# OpenTallas memory compiler (tools/mem_compiler), ASAP7 abstract view, track-aligned v2 (build_aligned_v2.py)
VERSION 5.7 ;
BUSBITCHARS "[]" ;
DIVIDERCHAR "/" ;
PROPERTYDEFINITIONS
  MACRO width INTEGER ;
  MACRO depth INTEGER ;
  MACRO banks INTEGER ;
END PROPERTYDEFINITIONS
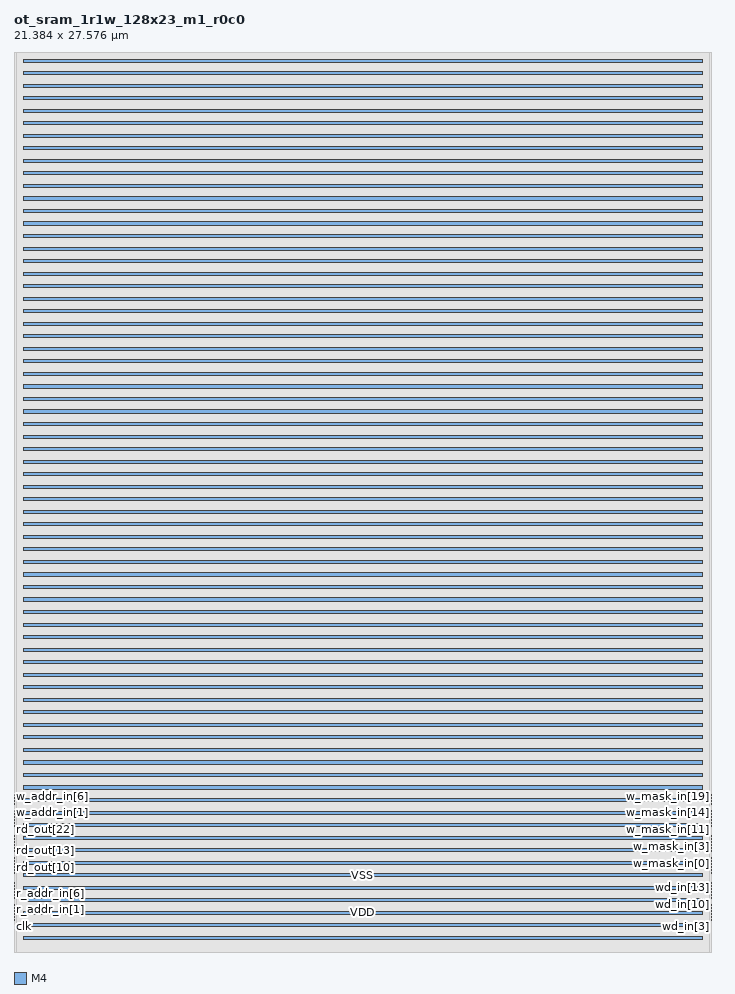
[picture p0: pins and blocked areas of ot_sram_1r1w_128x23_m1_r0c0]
MACRO ot_sram_1r1w_128x23_m1_r0c0
  PROPERTY width 23 ;
  PROPERTY depth 128 ;
  PROPERTY banks 1 ;
  FOREIGN ot_sram_1r1w_128x23_m1_r0c0 0 0 ;
  SYMMETRY X Y ;
  SIZE 21.384 BY 27.576 ;
  CLASS BLOCK ;
  PIN clk
    DIRECTION INPUT ;
    USE CLOCK ;
    SHAPE ABUTMENT ;
    PORT
      LAYER M4 ;
      RECT 0.000 0.768 0.024 0.792 ;
    END
  END clk
  PIN r_ce_in
    DIRECTION INPUT ;
    USE SIGNAL ;
    SHAPE ABUTMENT ;
    PORT
      LAYER M4 ;
      RECT 0.000 0.864 0.024 0.888 ;
    END
  END r_ce_in
  PIN r_addr_in[0]
    DIRECTION INPUT ;
    USE SIGNAL ;
    SHAPE ABUTMENT ;
    PORT
      LAYER M4 ;
      RECT 0.000 0.960 0.024 0.984 ;
    END
  END r_addr_in[0]
  PIN r_addr_in[1]
    DIRECTION INPUT ;
    USE SIGNAL ;
    SHAPE ABUTMENT ;
    PORT
      LAYER M4 ;
      RECT 0.000 1.056 0.024 1.080 ;
    END
  END r_addr_in[1]
  PIN r_addr_in[2]
    DIRECTION INPUT ;
    USE SIGNAL ;
    SHAPE ABUTMENT ;
    PORT
      LAYER M4 ;
      RECT 0.000 1.152 0.024 1.176 ;
    END
  END r_addr_in[2]
  PIN r_addr_in[3]
    DIRECTION INPUT ;
    USE SIGNAL ;
    SHAPE ABUTMENT ;
    PORT
      LAYER M4 ;
      RECT 0.000 1.248 0.024 1.272 ;
    END
  END r_addr_in[3]
  PIN r_addr_in[4]
    DIRECTION INPUT ;
    USE SIGNAL ;
    SHAPE ABUTMENT ;
    PORT
      LAYER M4 ;
      RECT 0.000 1.344 0.024 1.368 ;
    END
  END r_addr_in[4]
  PIN r_addr_in[5]
    DIRECTION INPUT ;
    USE SIGNAL ;
    SHAPE ABUTMENT ;
    PORT
      LAYER M4 ;
      RECT 0.000 1.440 0.024 1.464 ;
    END
  END r_addr_in[5]
  PIN r_addr_in[6]
    DIRECTION INPUT ;
    USE SIGNAL ;
    SHAPE ABUTMENT ;
    PORT
      LAYER M4 ;
      RECT 0.000 1.536 0.024 1.560 ;
    END
  END r_addr_in[6]
  PIN rd_out[0]
    DIRECTION OUTPUT ;
    USE SIGNAL ;
    SHAPE ABUTMENT ;
    PORT
      LAYER M4 ;
      RECT 0.000 1.632 0.024 1.656 ;
    END
  END rd_out[0]
  PIN rd_out[1]
    DIRECTION OUTPUT ;
    USE SIGNAL ;
    SHAPE ABUTMENT ;
    PORT
      LAYER M4 ;
      RECT 0.000 1.728 0.024 1.752 ;
    END
  END rd_out[1]
  PIN rd_out[2]
    DIRECTION OUTPUT ;
    USE SIGNAL ;
    SHAPE ABUTMENT ;
    PORT
      LAYER M4 ;
      RECT 0.000 1.824 0.024 1.848 ;
    END
  END rd_out[2]
  PIN rd_out[3]
    DIRECTION OUTPUT ;
    USE SIGNAL ;
    SHAPE ABUTMENT ;
    PORT
      LAYER M4 ;
      RECT 0.000 1.920 0.024 1.944 ;
    END
  END rd_out[3]
  PIN rd_out[4]
    DIRECTION OUTPUT ;
    USE SIGNAL ;
    SHAPE ABUTMENT ;
    PORT
      LAYER M4 ;
      RECT 0.000 2.016 0.024 2.040 ;
    END
  END rd_out[4]
  PIN rd_out[5]
    DIRECTION OUTPUT ;
    USE SIGNAL ;
    SHAPE ABUTMENT ;
    PORT
      LAYER M4 ;
      RECT 0.000 2.112 0.024 2.136 ;
    END
  END rd_out[5]
  PIN rd_out[6]
    DIRECTION OUTPUT ;
    USE SIGNAL ;
    SHAPE ABUTMENT ;
    PORT
      LAYER M4 ;
      RECT 0.000 2.208 0.024 2.232 ;
    END
  END rd_out[6]
  PIN rd_out[7]
    DIRECTION OUTPUT ;
    USE SIGNAL ;
    SHAPE ABUTMENT ;
    PORT
      LAYER M4 ;
      RECT 0.000 2.304 0.024 2.328 ;
    END
  END rd_out[7]
  PIN rd_out[8]
    DIRECTION OUTPUT ;
    USE SIGNAL ;
    SHAPE ABUTMENT ;
    PORT
      LAYER M4 ;
      RECT 0.000 2.400 0.024 2.424 ;
    END
  END rd_out[8]
  PIN rd_out[9]
    DIRECTION OUTPUT ;
    USE SIGNAL ;
    SHAPE ABUTMENT ;
    PORT
      LAYER M4 ;
      RECT 0.000 2.496 0.024 2.520 ;
    END
  END rd_out[9]
  PIN rd_out[10]
    DIRECTION OUTPUT ;
    USE SIGNAL ;
    SHAPE ABUTMENT ;
    PORT
      LAYER M4 ;
      RECT 0.000 2.592 0.024 2.616 ;
    END
  END rd_out[10]
  PIN rd_out[11]
    DIRECTION OUTPUT ;
    USE SIGNAL ;
    SHAPE ABUTMENT ;
    PORT
      LAYER M4 ;
      RECT 0.000 2.688 0.024 2.712 ;
    END
  END rd_out[11]
  PIN rd_out[12]
    DIRECTION OUTPUT ;
    USE SIGNAL ;
    SHAPE ABUTMENT ;
    PORT
      LAYER M4 ;
      RECT 0.000 2.784 0.024 2.808 ;
    END
  END rd_out[12]
  PIN rd_out[13]
    DIRECTION OUTPUT ;
    USE SIGNAL ;
    SHAPE ABUTMENT ;
    PORT
      LAYER M4 ;
      RECT 0.000 2.880 0.024 2.904 ;
    END
  END rd_out[13]
  PIN rd_out[14]
    DIRECTION OUTPUT ;
    USE SIGNAL ;
    SHAPE ABUTMENT ;
    PORT
      LAYER M4 ;
      RECT 0.000 2.976 0.024 3.000 ;
    END
  END rd_out[14]
  PIN rd_out[15]
    DIRECTION OUTPUT ;
    USE SIGNAL ;
    SHAPE ABUTMENT ;
    PORT
      LAYER M4 ;
      RECT 0.000 3.072 0.024 3.096 ;
    END
  END rd_out[15]
  PIN rd_out[16]
    DIRECTION OUTPUT ;
    USE SIGNAL ;
    SHAPE ABUTMENT ;
    PORT
      LAYER M4 ;
      RECT 0.000 3.168 0.024 3.192 ;
    END
  END rd_out[16]
  PIN rd_out[17]
    DIRECTION OUTPUT ;
    USE SIGNAL ;
    SHAPE ABUTMENT ;
    PORT
      LAYER M4 ;
      RECT 0.000 3.264 0.024 3.288 ;
    END
  END rd_out[17]
  PIN rd_out[18]
    DIRECTION OUTPUT ;
    USE SIGNAL ;
    SHAPE ABUTMENT ;
    PORT
      LAYER M4 ;
      RECT 0.000 3.360 0.024 3.384 ;
    END
  END rd_out[18]
  PIN rd_out[19]
    DIRECTION OUTPUT ;
    USE SIGNAL ;
    SHAPE ABUTMENT ;
    PORT
      LAYER M4 ;
      RECT 0.000 3.456 0.024 3.480 ;
    END
  END rd_out[19]
  PIN rd_out[20]
    DIRECTION OUTPUT ;
    USE SIGNAL ;
    SHAPE ABUTMENT ;
    PORT
      LAYER M4 ;
      RECT 0.000 3.552 0.024 3.576 ;
    END
  END rd_out[20]
  PIN rd_out[21]
    DIRECTION OUTPUT ;
    USE SIGNAL ;
    SHAPE ABUTMENT ;
    PORT
      LAYER M4 ;
      RECT 0.000 3.648 0.024 3.672 ;
    END
  END rd_out[21]
  PIN rd_out[22]
    DIRECTION OUTPUT ;
    USE SIGNAL ;
    SHAPE ABUTMENT ;
    PORT
      LAYER M4 ;
      RECT 0.000 3.744 0.024 3.768 ;
    END
  END rd_out[22]
  PIN w_ce_in
    DIRECTION INPUT ;
    USE SIGNAL ;
    SHAPE ABUTMENT ;
    PORT
      LAYER M4 ;
      RECT 0.000 3.840 0.024 3.864 ;
    END
  END w_ce_in
  PIN w_addr_in[0]
    DIRECTION INPUT ;
    USE SIGNAL ;
    SHAPE ABUTMENT ;
    PORT
      LAYER M4 ;
      RECT 0.000 3.936 0.024 3.960 ;
    END
  END w_addr_in[0]
  PIN w_addr_in[1]
    DIRECTION INPUT ;
    USE SIGNAL ;
    SHAPE ABUTMENT ;
    PORT
      LAYER M4 ;
      RECT 0.000 4.032 0.024 4.056 ;
    END
  END w_addr_in[1]
  PIN w_addr_in[2]
    DIRECTION INPUT ;
    USE SIGNAL ;
    SHAPE ABUTMENT ;
    PORT
      LAYER M4 ;
      RECT 0.000 4.128 0.024 4.152 ;
    END
  END w_addr_in[2]
  PIN w_addr_in[3]
    DIRECTION INPUT ;
    USE SIGNAL ;
    SHAPE ABUTMENT ;
    PORT
      LAYER M4 ;
      RECT 0.000 4.224 0.024 4.248 ;
    END
  END w_addr_in[3]
  PIN w_addr_in[4]
    DIRECTION INPUT ;
    USE SIGNAL ;
    SHAPE ABUTMENT ;
    PORT
      LAYER M4 ;
      RECT 0.000 4.320 0.024 4.344 ;
    END
  END w_addr_in[4]
  PIN w_addr_in[5]
    DIRECTION INPUT ;
    USE SIGNAL ;
    SHAPE ABUTMENT ;
    PORT
      LAYER M4 ;
      RECT 0.000 4.416 0.024 4.440 ;
    END
  END w_addr_in[5]
  PIN w_addr_in[6]
    DIRECTION INPUT ;
    USE SIGNAL ;
    SHAPE ABUTMENT ;
    PORT
      LAYER M4 ;
      RECT 0.000 4.512 0.024 4.536 ;
    END
  END w_addr_in[6]
  PIN wd_in[0]
    DIRECTION INPUT ;
    USE SIGNAL ;
    SHAPE ABUTMENT ;
    PORT
      LAYER M4 ;
      RECT 0.000 4.608 0.024 4.632 ;
    END
  END wd_in[0]
  PIN wd_in[1]
    DIRECTION INPUT ;
    USE SIGNAL ;
    SHAPE ABUTMENT ;
    PORT
      LAYER M4 ;
      RECT 0.000 4.704 0.024 4.728 ;
    END
  END wd_in[1]
  PIN wd_in[2]
    DIRECTION INPUT ;
    USE SIGNAL ;
    SHAPE ABUTMENT ;
    PORT
      LAYER M4 ;
      RECT 0.000 4.800 0.024 4.824 ;
    END
  END wd_in[2]
  PIN wd_in[3]
    DIRECTION INPUT ;
    USE SIGNAL ;
    SHAPE ABUTMENT ;
    PORT
      LAYER M4 ;
      RECT 21.360 0.768 21.384 0.792 ;
    END
  END wd_in[3]
  PIN wd_in[4]
    DIRECTION INPUT ;
    USE SIGNAL ;
    SHAPE ABUTMENT ;
    PORT
      LAYER M4 ;
      RECT 21.360 0.864 21.384 0.888 ;
    END
  END wd_in[4]
  PIN wd_in[5]
    DIRECTION INPUT ;
    USE SIGNAL ;
    SHAPE ABUTMENT ;
    PORT
      LAYER M4 ;
      RECT 21.360 0.960 21.384 0.984 ;
    END
  END wd_in[5]
  PIN wd_in[6]
    DIRECTION INPUT ;
    USE SIGNAL ;
    SHAPE ABUTMENT ;
    PORT
      LAYER M4 ;
      RECT 21.360 1.056 21.384 1.080 ;
    END
  END wd_in[6]
  PIN wd_in[7]
    DIRECTION INPUT ;
    USE SIGNAL ;
    SHAPE ABUTMENT ;
    PORT
      LAYER M4 ;
      RECT 21.360 1.152 21.384 1.176 ;
    END
  END wd_in[7]
  PIN wd_in[8]
    DIRECTION INPUT ;
    USE SIGNAL ;
    SHAPE ABUTMENT ;
    PORT
      LAYER M4 ;
      RECT 21.360 1.248 21.384 1.272 ;
    END
  END wd_in[8]
  PIN wd_in[9]
    DIRECTION INPUT ;
    USE SIGNAL ;
    SHAPE ABUTMENT ;
    PORT
      LAYER M4 ;
      RECT 21.360 1.344 21.384 1.368 ;
    END
  END wd_in[9]
  PIN wd_in[10]
    DIRECTION INPUT ;
    USE SIGNAL ;
    SHAPE ABUTMENT ;
    PORT
      LAYER M4 ;
      RECT 21.360 1.440 21.384 1.464 ;
    END
  END wd_in[10]
  PIN wd_in[11]
    DIRECTION INPUT ;
    USE SIGNAL ;
    SHAPE ABUTMENT ;
    PORT
      LAYER M4 ;
      RECT 21.360 1.536 21.384 1.560 ;
    END
  END wd_in[11]
  PIN wd_in[12]
    DIRECTION INPUT ;
    USE SIGNAL ;
    SHAPE ABUTMENT ;
    PORT
      LAYER M4 ;
      RECT 21.360 1.632 21.384 1.656 ;
    END
  END wd_in[12]
  PIN wd_in[13]
    DIRECTION INPUT ;
    USE SIGNAL ;
    SHAPE ABUTMENT ;
    PORT
      LAYER M4 ;
      RECT 21.360 1.728 21.384 1.752 ;
    END
  END wd_in[13]
  PIN wd_in[14]
    DIRECTION INPUT ;
    USE SIGNAL ;
    SHAPE ABUTMENT ;
    PORT
      LAYER M4 ;
      RECT 21.360 1.824 21.384 1.848 ;
    END
  END wd_in[14]
  PIN wd_in[15]
    DIRECTION INPUT ;
    USE SIGNAL ;
    SHAPE ABUTMENT ;
    PORT
      LAYER M4 ;
      RECT 21.360 1.920 21.384 1.944 ;
    END
  END wd_in[15]
  PIN wd_in[16]
    DIRECTION INPUT ;
    USE SIGNAL ;
    SHAPE ABUTMENT ;
    PORT
      LAYER M4 ;
      RECT 21.360 2.016 21.384 2.040 ;
    END
  END wd_in[16]
  PIN wd_in[17]
    DIRECTION INPUT ;
    USE SIGNAL ;
    SHAPE ABUTMENT ;
    PORT
      LAYER M4 ;
      RECT 21.360 2.112 21.384 2.136 ;
    END
  END wd_in[17]
  PIN wd_in[18]
    DIRECTION INPUT ;
    USE SIGNAL ;
    SHAPE ABUTMENT ;
    PORT
      LAYER M4 ;
      RECT 21.360 2.208 21.384 2.232 ;
    END
  END wd_in[18]
  PIN wd_in[19]
    DIRECTION INPUT ;
    USE SIGNAL ;
    SHAPE ABUTMENT ;
    PORT
      LAYER M4 ;
      RECT 21.360 2.304 21.384 2.328 ;
    END
  END wd_in[19]
  PIN wd_in[20]
    DIRECTION INPUT ;
    USE SIGNAL ;
    SHAPE ABUTMENT ;
    PORT
      LAYER M4 ;
      RECT 21.360 2.400 21.384 2.424 ;
    END
  END wd_in[20]
  PIN wd_in[21]
    DIRECTION INPUT ;
    USE SIGNAL ;
    SHAPE ABUTMENT ;
    PORT
      LAYER M4 ;
      RECT 21.360 2.496 21.384 2.520 ;
    END
  END wd_in[21]
  PIN wd_in[22]
    DIRECTION INPUT ;
    USE SIGNAL ;
    SHAPE ABUTMENT ;
    PORT
      LAYER M4 ;
      RECT 21.360 2.592 21.384 2.616 ;
    END
  END wd_in[22]
  PIN w_mask_in[0]
    DIRECTION INPUT ;
    USE SIGNAL ;
    SHAPE ABUTMENT ;
    PORT
      LAYER M4 ;
      RECT 21.360 2.688 21.384 2.712 ;
    END
  END w_mask_in[0]
  PIN w_mask_in[1]
    DIRECTION INPUT ;
    USE SIGNAL ;
    SHAPE ABUTMENT ;
    PORT
      LAYER M4 ;
      RECT 21.360 2.784 21.384 2.808 ;
    END
  END w_mask_in[1]
  PIN w_mask_in[2]
    DIRECTION INPUT ;
    USE SIGNAL ;
    SHAPE ABUTMENT ;
    PORT
      LAYER M4 ;
      RECT 21.360 2.880 21.384 2.904 ;
    END
  END w_mask_in[2]
  PIN w_mask_in[3]
    DIRECTION INPUT ;
    USE SIGNAL ;
    SHAPE ABUTMENT ;
    PORT
      LAYER M4 ;
      RECT 21.360 2.976 21.384 3.000 ;
    END
  END w_mask_in[3]
  PIN w_mask_in[4]
    DIRECTION INPUT ;
    USE SIGNAL ;
    SHAPE ABUTMENT ;
    PORT
      LAYER M4 ;
      RECT 21.360 3.072 21.384 3.096 ;
    END
  END w_mask_in[4]
  PIN w_mask_in[5]
    DIRECTION INPUT ;
    USE SIGNAL ;
    SHAPE ABUTMENT ;
    PORT
      LAYER M4 ;
      RECT 21.360 3.168 21.384 3.192 ;
    END
  END w_mask_in[5]
  PIN w_mask_in[6]
    DIRECTION INPUT ;
    USE SIGNAL ;
    SHAPE ABUTMENT ;
    PORT
      LAYER M4 ;
      RECT 21.360 3.264 21.384 3.288 ;
    END
  END w_mask_in[6]
  PIN w_mask_in[7]
    DIRECTION INPUT ;
    USE SIGNAL ;
    SHAPE ABUTMENT ;
    PORT
      LAYER M4 ;
      RECT 21.360 3.360 21.384 3.384 ;
    END
  END w_mask_in[7]
  PIN w_mask_in[8]
    DIRECTION INPUT ;
    USE SIGNAL ;
    SHAPE ABUTMENT ;
    PORT
      LAYER M4 ;
      RECT 21.360 3.456 21.384 3.480 ;
    END
  END w_mask_in[8]
  PIN w_mask_in[9]
    DIRECTION INPUT ;
    USE SIGNAL ;
    SHAPE ABUTMENT ;
    PORT
      LAYER M4 ;
      RECT 21.360 3.552 21.384 3.576 ;
    END
  END w_mask_in[9]
  PIN w_mask_in[10]
    DIRECTION INPUT ;
    USE SIGNAL ;
    SHAPE ABUTMENT ;
    PORT
      LAYER M4 ;
      RECT 21.360 3.648 21.384 3.672 ;
    END
  END w_mask_in[10]
  PIN w_mask_in[11]
    DIRECTION INPUT ;
    USE SIGNAL ;
    SHAPE ABUTMENT ;
    PORT
      LAYER M4 ;
      RECT 21.360 3.744 21.384 3.768 ;
    END
  END w_mask_in[11]
  PIN w_mask_in[12]
    DIRECTION INPUT ;
    USE SIGNAL ;
    SHAPE ABUTMENT ;
    PORT
      LAYER M4 ;
      RECT 21.360 3.840 21.384 3.864 ;
    END
  END w_mask_in[12]
  PIN w_mask_in[13]
    DIRECTION INPUT ;
    USE SIGNAL ;
    SHAPE ABUTMENT ;
    PORT
      LAYER M4 ;
      RECT 21.360 3.936 21.384 3.960 ;
    END
  END w_mask_in[13]
  PIN w_mask_in[14]
    DIRECTION INPUT ;
    USE SIGNAL ;
    SHAPE ABUTMENT ;
    PORT
      LAYER M4 ;
      RECT 21.360 4.032 21.384 4.056 ;
    END
  END w_mask_in[14]
  PIN w_mask_in[15]
    DIRECTION INPUT ;
    USE SIGNAL ;
    SHAPE ABUTMENT ;
    PORT
      LAYER M4 ;
      RECT 21.360 4.128 21.384 4.152 ;
    END
  END w_mask_in[15]
  PIN w_mask_in[16]
    DIRECTION INPUT ;
    USE SIGNAL ;
    SHAPE ABUTMENT ;
    PORT
      LAYER M4 ;
      RECT 21.360 4.224 21.384 4.248 ;
    END
  END w_mask_in[16]
  PIN w_mask_in[17]
    DIRECTION INPUT ;
    USE SIGNAL ;
    SHAPE ABUTMENT ;
    PORT
      LAYER M4 ;
      RECT 21.360 4.320 21.384 4.344 ;
    END
  END w_mask_in[17]
  PIN w_mask_in[18]
    DIRECTION INPUT ;
    USE SIGNAL ;
    SHAPE ABUTMENT ;
    PORT
      LAYER M4 ;
      RECT 21.360 4.416 21.384 4.440 ;
    END
  END w_mask_in[18]
  PIN w_mask_in[19]
    DIRECTION INPUT ;
    USE SIGNAL ;
    SHAPE ABUTMENT ;
    PORT
      LAYER M4 ;
      RECT 21.360 4.512 21.384 4.536 ;
    END
  END w_mask_in[19]
  PIN w_mask_in[20]
    DIRECTION INPUT ;
    USE SIGNAL ;
    SHAPE ABUTMENT ;
    PORT
      LAYER M4 ;
      RECT 21.360 4.608 21.384 4.632 ;
    END
  END w_mask_in[20]
  PIN w_mask_in[21]
    DIRECTION INPUT ;
    USE SIGNAL ;
    SHAPE ABUTMENT ;
    PORT
      LAYER M4 ;
      RECT 21.360 4.704 21.384 4.728 ;
    END
  END w_mask_in[21]
  PIN w_mask_in[22]
    DIRECTION INPUT ;
    USE SIGNAL ;
    SHAPE ABUTMENT ;
    PORT
      LAYER M4 ;
      RECT 21.360 4.800 21.384 4.824 ;
    END
  END w_mask_in[22]
  PIN VDD
    DIRECTION INOUT ;
    USE POWER ;
    PORT
      LAYER M4 ;
      RECT 0.300 0.384 21.084 0.480 ;
      RECT 0.300 1.152 21.084 1.248 ;
      RECT 0.300 1.920 21.084 2.016 ;
      RECT 0.300 2.688 21.084 2.784 ;
      RECT 0.300 3.456 21.084 3.552 ;
      RECT 0.300 4.224 21.084 4.320 ;
      RECT 0.300 4.992 21.084 5.088 ;
      RECT 0.300 5.760 21.084 5.856 ;
      RECT 0.300 6.528 21.084 6.624 ;
      RECT 0.300 7.296 21.084 7.392 ;
      RECT 0.300 8.064 21.084 8.160 ;
      RECT 0.300 8.832 21.084 8.928 ;
      RECT 0.300 9.600 21.084 9.696 ;
      RECT 0.300 10.368 21.084 10.464 ;
      RECT 0.300 11.136 21.084 11.232 ;
      RECT 0.300 11.904 21.084 12.000 ;
      RECT 0.300 12.672 21.084 12.768 ;
      RECT 0.300 13.440 21.084 13.536 ;
      RECT 0.300 14.208 21.084 14.304 ;
      RECT 0.300 14.976 21.084 15.072 ;
      RECT 0.300 15.744 21.084 15.840 ;
      RECT 0.300 16.512 21.084 16.608 ;
      RECT 0.300 17.280 21.084 17.376 ;
      RECT 0.300 18.048 21.084 18.144 ;
      RECT 0.300 18.816 21.084 18.912 ;
      RECT 0.300 19.584 21.084 19.680 ;
      RECT 0.300 20.352 21.084 20.448 ;
      RECT 0.300 21.120 21.084 21.216 ;
      RECT 0.300 21.888 21.084 21.984 ;
      RECT 0.300 22.656 21.084 22.752 ;
      RECT 0.300 23.424 21.084 23.520 ;
      RECT 0.300 24.192 21.084 24.288 ;
      RECT 0.300 24.960 21.084 25.056 ;
      RECT 0.300 25.728 21.084 25.824 ;
      RECT 0.300 26.496 21.084 26.592 ;
      RECT 0.300 27.264 21.084 27.360 ;
    END
  END VDD
  PIN VSS
    DIRECTION INOUT ;
    USE GROUND ;
    PORT
      LAYER M4 ;
      RECT 0.300 0.768 21.084 0.864 ;
      RECT 0.300 1.536 21.084 1.632 ;
      RECT 0.300 2.304 21.084 2.400 ;
      RECT 0.300 3.072 21.084 3.168 ;
      RECT 0.300 3.840 21.084 3.936 ;
      RECT 0.300 4.608 21.084 4.704 ;
      RECT 0.300 5.376 21.084 5.472 ;
      RECT 0.300 6.144 21.084 6.240 ;
      RECT 0.300 6.912 21.084 7.008 ;
      RECT 0.300 7.680 21.084 7.776 ;
      RECT 0.300 8.448 21.084 8.544 ;
      RECT 0.300 9.216 21.084 9.312 ;
      RECT 0.300 9.984 21.084 10.080 ;
      RECT 0.300 10.752 21.084 10.848 ;
      RECT 0.300 11.520 21.084 11.616 ;
      RECT 0.300 12.288 21.084 12.384 ;
      RECT 0.300 13.056 21.084 13.152 ;
      RECT 0.300 13.824 21.084 13.920 ;
      RECT 0.300 14.592 21.084 14.688 ;
      RECT 0.300 15.360 21.084 15.456 ;
      RECT 0.300 16.128 21.084 16.224 ;
      RECT 0.300 16.896 21.084 16.992 ;
      RECT 0.300 17.664 21.084 17.760 ;
      RECT 0.300 18.432 21.084 18.528 ;
      RECT 0.300 19.200 21.084 19.296 ;
      RECT 0.300 19.968 21.084 20.064 ;
      RECT 0.300 20.736 21.084 20.832 ;
      RECT 0.300 21.504 21.084 21.600 ;
      RECT 0.300 22.272 21.084 22.368 ;
      RECT 0.300 23.040 21.084 23.136 ;
      RECT 0.300 23.808 21.084 23.904 ;
      RECT 0.300 24.576 21.084 24.672 ;
      RECT 0.300 25.344 21.084 25.440 ;
      RECT 0.300 26.112 21.084 26.208 ;
      RECT 0.300 26.880 21.084 26.976 ;
    END
  END VSS
  OBS
    LAYER M1 ;
    RECT 0 0 21.384 27.576 ;
    LAYER M2 ;
    RECT 0 0 21.384 27.576 ;
    LAYER M3 ;
    RECT 0 0 21.384 27.576 ;
    LAYER M4 ;
    RECT 0.072 0 21.312 27.576 ;
  END
END ot_sram_1r1w_128x23_m1_r0c0

END LIBRARY
